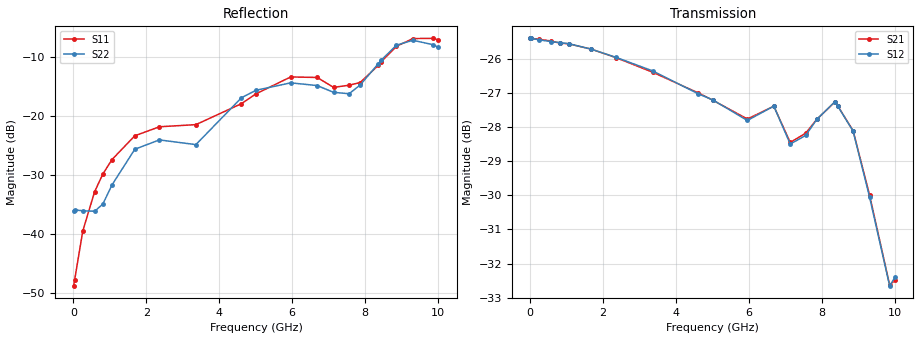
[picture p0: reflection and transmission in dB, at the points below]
! Device ID: PE43704
! Dir: z:\PE43704\PE43704_Char_1_20130516\PE43704\AMB\3p400V\24p50dB
! Serial: 14
! Insertion: A
! Impedance: 50 ohm
! Temp: Amb
! VDD: 3.400V
! Attenuation Step: 24.50dB
! IDD: 1.140487e-01mA
#  Hz  S  RI  R  50
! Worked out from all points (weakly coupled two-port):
!   401 points, 10 MHz to 10.01 GHz, reference 50 ohm
!   highest |S21| = -25.40 dB at 35 MHz (marker M1); lowest = -32.6 dB at 9.86 GHz (marker M2)
!   lowest |S11| = -48.7 dB at 10 MHz (marker M3), VSWR 1.01, Z = 50.4 + j0.0371 ohm
!   |S11| at or under -10 dB: start of sweep to 8.563 GHz
!   |S22| runs from -36.3 to -7.2 dB; largest |S21 - S12| = 0.00079
!   S11 on the Smith chart (normalised r, x): 10 MHz: 1.01, +0.00; 4.61 GHz: 0.79, +0.08; 8.435 GHz: 0.76, +0.46; 9.31 GHz: 0.51, +0.52; 10.01 GHz: 0.44, +0.31
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1e7  0.00366 0.000368  0.0537 -0.000139  0.0537 -0.000158  0.0158 0.000277
3.5e7  0.00378 0.00155  0.0537 -0.000499  0.0537 -0.000536  0.016 0.00113
2.6e8  0.00119 0.0106  0.0534 -0.00372  0.0533 -0.00367  0.0133 0.0085
5.85e8  -0.0096 0.0208  0.0526 -0.00806  0.0525 -0.00803  0.00267 0.0154
8.1e8  -0.0213 0.0242  0.0517 -0.011  0.0518 -0.011  -0.00823 0.016
1.06e9  -0.0359 0.0231  0.0508 -0.0141  0.0508 -0.0142  -0.0227 0.0128
1.685e9  -0.0675 0.00642  0.0471 -0.0215  0.0471 -0.0215  -0.0515 -0.0084
2.36e9  -0.0795 -0.0143  0.0418 -0.028  0.0418 -0.0281  -0.0572 -0.0254
3.36e9  -0.0835 -0.0108  0.0324 -0.0353  0.0325 -0.0355  -0.057 -0.00354
4.61e9  -0.1165 0.0495  0.0207 -0.0396  0.0206 -0.0395  -0.1281 0.0614
5.01e9  -0.136 0.071  0.0178 -0.0398  0.0179 -0.0398  -0.1505 0.0661
5.96e9  -0.1866 0.1024  0.00987 -0.0397  0.00985 -0.0395  -0.173 0.0779
6.685e9  -0.1875 0.0961  0.00528 -0.0424  0.00531 -0.0424  -0.1573 0.0876
7.135e9  -0.1547 0.0793  -0.000419 -0.0378  -0.000423 -0.0376  -0.1149 0.1082
7.56e9  -0.1297 0.1267  -0.000624 -0.039  -0.000655 -0.0387  -0.0733 0.135
7.86e9  -0.0941 0.1657  -0.00217 -0.0408  -0.00195 -0.0408  -0.0598 0.1712
8.36e9  -0.0596 0.2595  -0.0114 -0.0418  -0.0112 -0.0419  -0.0659 0.2671
8.435e9  -0.0609 0.2784  -0.0129 -0.0408  -0.0128 -0.0408  -0.0727 0.2843
8.86e9  -0.1009 0.3728  -0.0194 -0.0342  -0.0191 -0.0343  -0.1199 0.3764
9.31e9  -0.1826 0.4101  -0.0182 -0.0259  -0.0184 -0.0255  -0.1939 0.3884
9.86e9  -0.3027 0.3338  -0.00919 -0.0215  -0.00926 -0.0214  -0.2943 0.2688
1.001e10  -0.3285 0.2888  -0.0059 -0.023  -0.00608 -0.0232  -0.3118 0.2163
